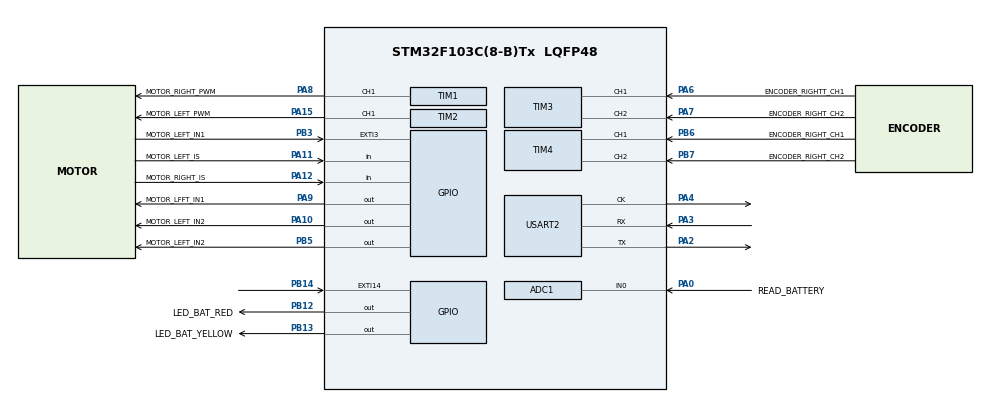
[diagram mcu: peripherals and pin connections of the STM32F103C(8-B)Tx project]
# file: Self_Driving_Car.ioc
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ADC1.Channel-0\#ChannelRegularConversion=ADC_CHANNEL_0
ADC1.NbrOfConversionFlag=1
ADC1.Rank-0\#ChannelRegularConversion=1
ADC1.SamplingTime-0\#ChannelRegularConversion=ADC_SAMPLETIME_1CYCLE_5
ADC1.master=1
Mcu.Family=STM32F1
Mcu.Name=STM32F103C(8-B)Tx
Mcu.Package=LQFP48
NVIC.ADC1_2_IRQn=true\:0\:0\:false\:false\:true\:true\:true\:true
NVIC.PriorityGroup=NVIC_PRIORITYGROUP_4
NVIC.USART2_IRQn=true\:0\:0\:false\:false\:true\:true\:true\:true
PA0-WKUP.GPIO_Label=READ_BATTERY
PA0-WKUP.Signal=ADCx_IN0
PA10.GPIO_Label=MOTOR_LEFT_IN2
PA10.Signal=GPIO_Output
PA11.GPIO_Label=MOTOR_LEFT_IS
PA11.Signal=GPIO_Input
PA12.GPIO_Label=MOTOR_RIGHT_IS
PA12.Signal=GPIO_Input
PA13.Mode=Serial_Wire
PA13.Signal=SYS_JTMS-SWDIO
PA14.Mode=Serial_Wire
PA14.Signal=SYS_JTCK-SWCLK
PA15.GPIO_Label=MOTOR_LEFT_PWM
PA15.Signal=S_TIM2_CH1_ETR
PA2.Mode=Synchronous
PA2.Signal=USART2_TX
PA3.Mode=Synchronous
PA3.Signal=USART2_RX
PA4.Mode=Synchronous
PA4.Signal=USART2_CK
PA6.GPIO_Label=ENCODER_RIGHTT_CH1
PA6.Signal=S_TIM3_CH1
PA7.GPIO_Label=ENCODER_RIGHT_CH2
PA7.Signal=S_TIM3_CH2
PA8.GPIO_Label=MOTOR_RIGHT_PWM
PA8.Signal=S_TIM1_CH1
PA9.GPIO_Label=MOTOR_LFFT_IN1
PA9.Signal=GPIO_Output
PB12.GPIO_Label=LED_BAT_RED
PB12.Signal=GPIO_Output
PB13.GPIO_Label=LED_BAT_YELLOW
PB13.Signal=GPIO_Output
PB14.Signal=GPXTI14
PB3.GPIO_Label=MOTOR_LEFT_IN1
PB3.Signal=GPXTI3
PB5.GPIO_Label=MOTOR_LEFT_IN2
PB5.Signal=GPIO_Output
PB6.GPIO_Label=ENCODER_RIGHT_CH1
PB6.Signal=S_TIM4_CH1
PB7.GPIO_Label=ENCODER_RIGHT_CH2
PB7.Signal=S_TIM4_CH2
PD0-OSC_IN.Mode=HSE-External-Oscillator
PD0-OSC_IN.Signal=RCC_OSC_IN
PD1-OSC_OUT.Mode=HSE-External-Oscillator
PD1-OSC_OUT.Signal=RCC_OSC_OUT
ProjectManager.HeapSize=0x200
ProjectManager.StackSize=0x400
ProjectManager.TargetToolchain=STM32CubeIDE
RCC.APB1Freq_Value=8000000
RCC.APB2Freq_Value=8000000
SH.ADCx_IN0.0=ADC1_IN0,IN0
SH.S_TIM1_CH1.0=TIM1_CH1,PWM Generation1 CH1
SH.S_TIM2_CH1_ETR.0=TIM2_CH1,PWM Generation1 CH1
SH.S_TIM3_CH1.0=TIM3_CH1,Encoder_Interface
SH.S_TIM3_CH2.0=TIM3_CH2,Encoder_Interface
SH.S_TIM4_CH1.0=TIM4_CH1,Encoder_Interface
SH.S_TIM4_CH2.0=TIM4_CH2,Encoder_Interface
TIM1.Channel-PWM\ Generation1\ CH1=TIM_CHANNEL_1
TIM2.Channel-PWM\ Generation1\ CH1=TIM_CHANNEL_1
TIM4.EncoderMode=TIM_ENCODERMODE_TI12
USART2.VirtualMode=VM_SYNC
board=custom

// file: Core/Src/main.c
/* USER CODE BEGIN Header */
/**
  ******************************************************************************
  * @file           : main.c
  * @brief          : Main program body
  ******************************************************************************
  * @attention
  *
  * Copyright (c) 2024 STMicroelectronics.
  * All rights reserved.
  *
  * This software is licensed under terms that can be found in the LICENSE file
  * in the root directory of this software component.
  * If no LICENSE file comes with this software, it is provided AS-IS.
  *
  ******************************************************************************
  */
/* USER CODE END Header */
#include "main.h"

ADC_HandleTypeDef hadc1;

TIM_HandleTypeDef htim1;
TIM_HandleTypeDef htim2;
TIM_HandleTypeDef htim3;
TIM_HandleTypeDef htim4;

USART_HandleTypeDef husart2;

/* USER CODE BEGIN PV */
char Rx_data[2];
char subRx_data[2];
char transfer_cplt;
int i;
int length;
int v;

/* USER CODE END PV */

void SystemClock_Config(void);
static void MX_GPIO_Init(void);
static void MX_TIM1_Init(void);
static void MX_TIM2_Init(void);
static void MX_TIM3_Init(void);
static void MX_USART2_Init(void);
static void MX_ADC1_Init(void);
static void MX_TIM4_Init(void);

int main(void)
{

  /* MCU Configuration--------------------------------------------------------*/

  /* Reset of all peripherals, Initializes the Flash interface and the Systick. */
  HAL_Init();

  /* Configure the system clock */
  SystemClock_Config();

  /* Initialize all configured peripherals */
  MX_GPIO_Init();
  MX_TIM1_Init();
  MX_TIM2_Init();
  MX_TIM3_Init();
  MX_USART2_Init();
  MX_ADC1_Init();
  MX_TIM4_Init();

  /* Infinite loop */
  while (1)
  {

  }
}

void SystemClock_Config(void)
{
  RCC_OscInitTypeDef RCC_OscInitStruct = {0};
  RCC_ClkInitTypeDef RCC_ClkInitStruct = {0};
  RCC_PeriphCLKInitTypeDef PeriphClkInit = {0};

  /** Initializes the RCC Oscillators according to the specified parameters
  * in the RCC_OscInitTypeDef structure.
  */
  RCC_OscInitStruct.OscillatorType = RCC_OSCILLATORTYPE_HSI;
  RCC_OscInitStruct.HSIState = RCC_HSI_ON;
  RCC_OscInitStruct.HSICalibrationValue = RCC_HSICALIBRATION_DEFAULT;
  RCC_OscInitStruct.PLL.PLLState = RCC_PLL_NONE;
  if (HAL_RCC_OscConfig(&RCC_OscInitStruct) != HAL_OK)
  {
    Error_Handler();
  }

  /** Initializes the CPU, AHB and APB buses clocks
  */
  RCC_ClkInitStruct.ClockType = RCC_CLOCKTYPE_HCLK|RCC_CLOCKTYPE_SYSCLK
                              |RCC_CLOCKTYPE_PCLK1|RCC_CLOCKTYPE_PCLK2;
  RCC_ClkInitStruct.SYSCLKSource = RCC_SYSCLKSOURCE_HSI;
  RCC_ClkInitStruct.AHBCLKDivider = RCC_SYSCLK_DIV1;
  RCC_ClkInitStruct.APB1CLKDivider = RCC_HCLK_DIV1;
  RCC_ClkInitStruct.APB2CLKDivider = RCC_HCLK_DIV1;

  if (HAL_RCC_ClockConfig(&RCC_ClkInitStruct, FLASH_LATENCY_0) != HAL_OK)
  {
    Error_Handler();
  }
  PeriphClkInit.PeriphClockSelection = RCC_PERIPHCLK_ADC;
  PeriphClkInit.AdcClockSelection = RCC_ADCPCLK2_DIV2;
  if (HAL_RCCEx_PeriphCLKConfig(&PeriphClkInit) != HAL_OK)
  {
    Error_Handler();
  }
}

static void MX_ADC1_Init(void)
{

  ADC_ChannelConfTypeDef sConfig = {0};

  /** Common config
  */
  hadc1.Instance = ADC1;
  hadc1.Init.ScanConvMode = ADC_SCAN_DISABLE;
  hadc1.Init.ContinuousConvMode = DISABLE;
  hadc1.Init.DiscontinuousConvMode = DISABLE;
  hadc1.Init.ExternalTrigConv = ADC_SOFTWARE_START;
  hadc1.Init.DataAlign = ADC_DATAALIGN_RIGHT;
  hadc1.Init.NbrOfConversion = 1;
  if (HAL_ADC_Init(&hadc1) != HAL_OK)
  {
    Error_Handler();
  }

  /** Configure Regular Channel
  */
  sConfig.Channel = ADC_CHANNEL_0;
  sConfig.Rank = ADC_REGULAR_RANK_1;
  sConfig.SamplingTime = ADC_SAMPLETIME_1CYCLE_5;
  if (HAL_ADC_ConfigChannel(&hadc1, &sConfig) != HAL_OK)
  {
    Error_Handler();
  }

}

static void MX_TIM1_Init(void)
{

  TIM_MasterConfigTypeDef sMasterConfig = {0};
  TIM_OC_InitTypeDef sConfigOC = {0};
  TIM_BreakDeadTimeConfigTypeDef sBreakDeadTimeConfig = {0};

  htim1.Instance = TIM1;
  htim1.Init.Prescaler = 0;
  htim1.Init.CounterMode = TIM_COUNTERMODE_UP;
  htim1.Init.Period = 65535;
  htim1.Init.ClockDivision = TIM_CLOCKDIVISION_DIV1;
  htim1.Init.RepetitionCounter = 0;
  htim1.Init.AutoReloadPreload = TIM_AUTORELOAD_PRELOAD_DISABLE;
  if (HAL_TIM_PWM_Init(&htim1) != HAL_OK)
  {
    Error_Handler();
  }
  sMasterConfig.MasterOutputTrigger = TIM_TRGO_RESET;
  sMasterConfig.MasterSlaveMode = TIM_MASTERSLAVEMODE_DISABLE;
  if (HAL_TIMEx_MasterConfigSynchronization(&htim1, &sMasterConfig) != HAL_OK)
  {
    Error_Handler();
  }
  sConfigOC.OCMode = TIM_OCMODE_PWM1;
  sConfigOC.Pulse = 0;
  sConfigOC.OCPolarity = TIM_OCPOLARITY_HIGH;
  sConfigOC.OCNPolarity = TIM_OCNPOLARITY_HIGH;
  sConfigOC.OCFastMode = TIM_OCFAST_DISABLE;
  sConfigOC.OCIdleState = TIM_OCIDLESTATE_RESET;
  sConfigOC.OCNIdleState = TIM_OCNIDLESTATE_RESET;
  if (HAL_TIM_PWM_ConfigChannel(&htim1, &sConfigOC, TIM_CHANNEL_1) != HAL_OK)
  {
    Error_Handler();
  }
  sBreakDeadTimeConfig.OffStateRunMode = TIM_OSSR_DISABLE;
  sBreakDeadTimeConfig.OffStateIDLEMode = TIM_OSSI_DISABLE;
  sBreakDeadTimeConfig.LockLevel = TIM_LOCKLEVEL_OFF;
  sBreakDeadTimeConfig.DeadTime = 0;
  sBreakDeadTimeConfig.BreakState = TIM_BREAK_DISABLE;
  sBreakDeadTimeConfig.BreakPolarity = TIM_BREAKPOLARITY_HIGH;
  sBreakDeadTimeConfig.AutomaticOutput = TIM_AUTOMATICOUTPUT_DISABLE;
  if (HAL_TIMEx_ConfigBreakDeadTime(&htim1, &sBreakDeadTimeConfig) != HAL_OK)
  {
    Error_Handler();
  }
  HAL_TIM_MspPostInit(&htim1);

}

static void MX_TIM2_Init(void)
{

  TIM_MasterConfigTypeDef sMasterConfig = {0};
  TIM_OC_InitTypeDef sConfigOC = {0};

  htim2.Instance = TIM2;
  htim2.Init.Prescaler = 0;
  htim2.Init.CounterMode = TIM_COUNTERMODE_UP;
  htim2.Init.Period = 65535;
  htim2.Init.ClockDivision = TIM_CLOCKDIVISION_DIV1;
  htim2.Init.AutoReloadPreload = TIM_AUTORELOAD_PRELOAD_DISABLE;
  if (HAL_TIM_PWM_Init(&htim2) != HAL_OK)
  {
    Error_Handler();
  }
  sMasterConfig.MasterOutputTrigger = TIM_TRGO_RESET;
  sMasterConfig.MasterSlaveMode = TIM_MASTERSLAVEMODE_DISABLE;
  if (HAL_TIMEx_MasterConfigSynchronization(&htim2, &sMasterConfig) != HAL_OK)
  {
    Error_Handler();
  }
  sConfigOC.OCMode = TIM_OCMODE_PWM1;
  sConfigOC.Pulse = 0;
  sConfigOC.OCPolarity = TIM_OCPOLARITY_HIGH;
  sConfigOC.OCFastMode = TIM_OCFAST_DISABLE;
  if (HAL_TIM_PWM_ConfigChannel(&htim2, &sConfigOC, TIM_CHANNEL_1) != HAL_OK)
  {
    Error_Handler();
  }
  HAL_TIM_MspPostInit(&htim2);

}

static void MX_TIM3_Init(void)
{

  TIM_Encoder_InitTypeDef sConfig = {0};
  TIM_MasterConfigTypeDef sMasterConfig = {0};

  htim3.Instance = TIM3;
  htim3.Init.Prescaler = 0;
  htim3.Init.CounterMode = TIM_COUNTERMODE_UP;
  htim3.Init.Period = 65535;
  htim3.Init.ClockDivision = TIM_CLOCKDIVISION_DIV1;
  htim3.Init.AutoReloadPreload = TIM_AUTORELOAD_PRELOAD_DISABLE;
  sConfig.EncoderMode = TIM_ENCODERMODE_TI1;
  sConfig.IC1Polarity = TIM_ICPOLARITY_RISING;
  sConfig.IC1Selection = TIM_ICSELECTION_DIRECTTI;
  sConfig.IC1Prescaler = TIM_ICPSC_DIV1;
  sConfig.IC1Filter = 0;
  sConfig.IC2Polarity = TIM_ICPOLARITY_RISING;
  sConfig.IC2Selection = TIM_ICSELECTION_DIRECTTI;
  sConfig.IC2Prescaler = TIM_ICPSC_DIV1;
  sConfig.IC2Filter = 0;
  if (HAL_TIM_Encoder_Init(&htim3, &sConfig) != HAL_OK)
  {
    Error_Handler();
  }
  sMasterConfig.MasterOutputTrigger = TIM_TRGO_RESET;
  sMasterConfig.MasterSlaveMode = TIM_MASTERSLAVEMODE_DISABLE;
  if (HAL_TIMEx_MasterConfigSynchronization(&htim3, &sMasterConfig) != HAL_OK)
  {
    Error_Handler();
  }

}

static void MX_TIM4_Init(void)
{

  TIM_Encoder_InitTypeDef sConfig = {0};
  TIM_MasterConfigTypeDef sMasterConfig = {0};

  htim4.Instance = TIM4;
  htim4.Init.Prescaler = 0;
  htim4.Init.CounterMode = TIM_COUNTERMODE_UP;
  htim4.Init.Period = 65535;
  htim4.Init.ClockDivision = TIM_CLOCKDIVISION_DIV1;
  htim4.Init.AutoReloadPreload = TIM_AUTORELOAD_PRELOAD_DISABLE;
  sConfig.EncoderMode = TIM_ENCODERMODE_TI12;
  sConfig.IC1Polarity = TIM_ICPOLARITY_RISING;
  sConfig.IC1Selection = TIM_ICSELECTION_DIRECTTI;
  sConfig.IC1Prescaler = TIM_ICPSC_DIV1;
  sConfig.IC1Filter = 0;
  sConfig.IC2Polarity = TIM_ICPOLARITY_RISING;
  sConfig.IC2Selection = TIM_ICSELECTION_DIRECTTI;
  sConfig.IC2Prescaler = TIM_ICPSC_DIV1;
  sConfig.IC2Filter = 0;
  if (HAL_TIM_Encoder_Init(&htim4, &sConfig) != HAL_OK)
  {
    Error_Handler();
  }
  sMasterConfig.MasterOutputTrigger = TIM_TRGO_RESET;
  sMasterConfig.MasterSlaveMode = TIM_MASTERSLAVEMODE_DISABLE;
  if (HAL_TIMEx_MasterConfigSynchronization(&htim4, &sMasterConfig) != HAL_OK)
  {
    Error_Handler();
  }

}

static void MX_USART2_Init(void)
{

  husart2.Instance = USART2;
  husart2.Init.BaudRate = 115200;
  husart2.Init.WordLength = USART_WORDLENGTH_8B;
  husart2.Init.StopBits = USART_STOPBITS_1;
  husart2.Init.Parity = USART_PARITY_NONE;
  husart2.Init.Mode = USART_MODE_TX_RX;
  husart2.Init.CLKPolarity = USART_POLARITY_LOW;
  husart2.Init.CLKPhase = USART_PHASE_1EDGE;
  husart2.Init.CLKLastBit = USART_LASTBIT_DISABLE;
  if (HAL_USART_Init(&husart2) != HAL_OK)
  {
    Error_Handler();
  }

}

static void MX_GPIO_Init(void)
{
  GPIO_InitTypeDef GPIO_InitStruct = {0};

  /* GPIO Ports Clock Enable */
  __HAL_RCC_GPIOD_CLK_ENABLE();
  __HAL_RCC_GPIOA_CLK_ENABLE();
  __HAL_RCC_GPIOB_CLK_ENABLE();

  /*Configure GPIO pin Output Level */
  HAL_GPIO_WritePin(GPIOB, LED_BAT_RED_Pin|LED_BAT_YELLOW_Pin|MOTOR_LEFT_IN2_Pin, GPIO_PIN_RESET);

  /*Configure GPIO pin Output Level */
  HAL_GPIO_WritePin(GPIOA, MOTOR_RIGHT_IN1_Pin|MOTOR_RIGHT_IN2_Pin, GPIO_PIN_RESET);

  /*Configure GPIO pins : LED_BAT_RED_Pin LED_BAT_YELLOW_Pin MOTOR_LEFT_IN2_Pin */
  GPIO_InitStruct.Pin = LED_BAT_RED_Pin|LED_BAT_YELLOW_Pin|MOTOR_LEFT_IN2_Pin;
  GPIO_InitStruct.Mode = GPIO_MODE_OUTPUT_PP;
  GPIO_InitStruct.Pull = GPIO_NOPULL;
  GPIO_InitStruct.Speed = GPIO_SPEED_FREQ_LOW;
  HAL_GPIO_Init(GPIOB, &GPIO_InitStruct);

  /*Configure GPIO pins : PB14 MOTOR_LEFT_IN1_Pin */
  GPIO_InitStruct.Pin = GPIO_PIN_14|MOTOR_LEFT_IN1_Pin;
  GPIO_InitStruct.Mode = GPIO_MODE_IT_RISING;
  GPIO_InitStruct.Pull = GPIO_NOPULL;
  HAL_GPIO_Init(GPIOB, &GPIO_InitStruct);

  /*Configure GPIO pins : MOTOR_RIGHT_IN1_Pin MOTOR_RIGHT_IN2_Pin */
  GPIO_InitStruct.Pin = MOTOR_RIGHT_IN1_Pin|MOTOR_RIGHT_IN2_Pin;
  GPIO_InitStruct.Mode = GPIO_MODE_OUTPUT_PP;
  GPIO_InitStruct.Pull = GPIO_NOPULL;
  GPIO_InitStruct.Speed = GPIO_SPEED_FREQ_LOW;
  HAL_GPIO_Init(GPIOA, &GPIO_InitStruct);

  /*Configure GPIO pins : MOTOR_LEFT_IS_Pin MOTOR_RIGHT_IS_Pin */
  GPIO_InitStruct.Pin = MOTOR_LEFT_IS_Pin|MOTOR_RIGHT_IS_Pin;
  GPIO_InitStruct.Mode = GPIO_MODE_INPUT;
  GPIO_InitStruct.Pull = GPIO_NOPULL;
  HAL_GPIO_Init(GPIOA, &GPIO_InitStruct);

}

void Error_Handler(void)
{
  __disable_irq();
  while (1)
  {
  }
}
